VERSION 5.7 ;
  NOWIREEXTENSIONATPIN ON ;
  DIVIDERCHAR "/" ;
  BUSBITCHARS "[]" ;
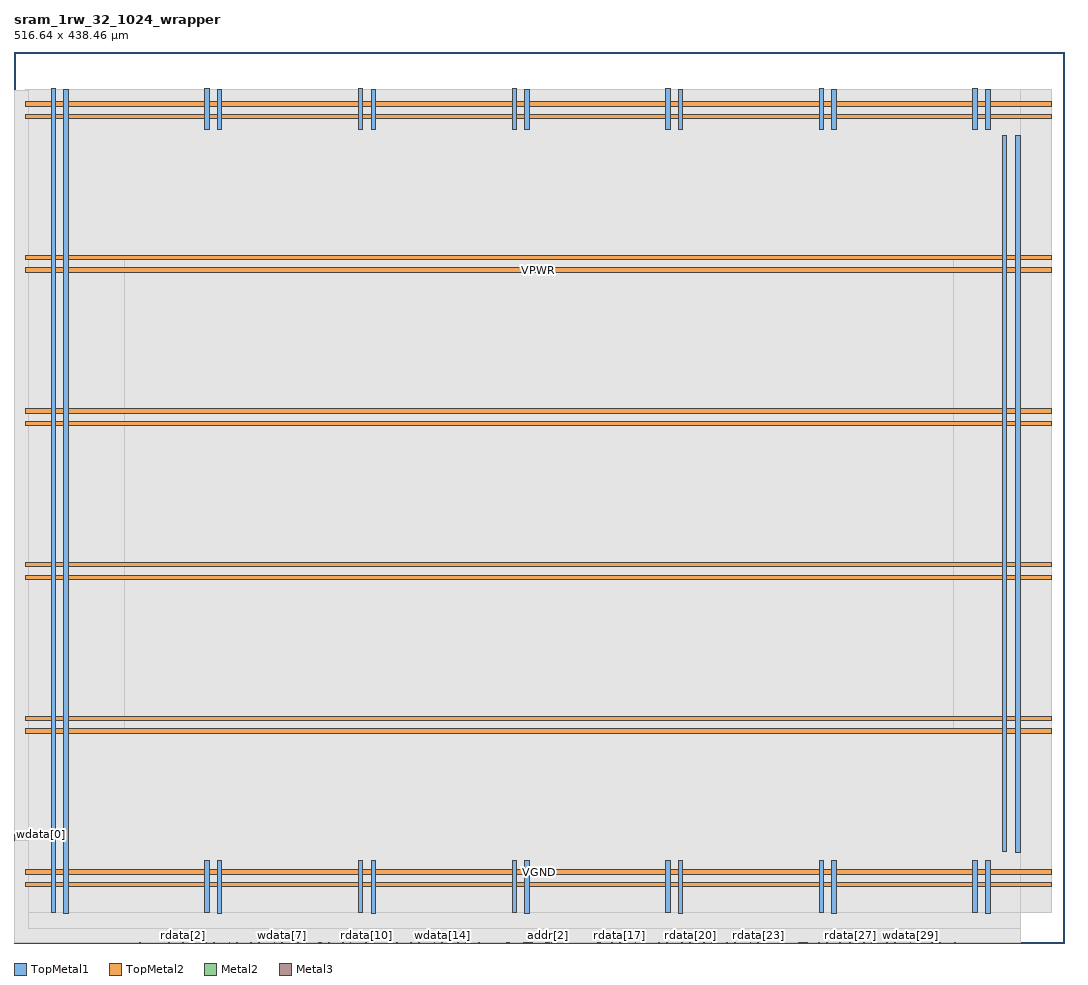
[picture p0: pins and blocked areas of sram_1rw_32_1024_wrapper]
MACRO sram_1rw_32_1024_wrapper
  CLASS BLOCK ;
  FOREIGN sram_1rw_32_1024_wrapper ;
  ORIGIN 0.000 0.000 ;
  SIZE 516.640 BY 438.460 ;
  PIN VGND
    DIRECTION INOUT ;
    USE GROUND ;
    PORT
      LAYER TopMetal1 ;
        RECT 24.460 14.490 26.660 419.800 ;
    END
    PORT
      LAYER TopMetal1 ;
        RECT 100.060 14.490 102.260 40.360 ;
    END
    PORT
      LAYER TopMetal1 ;
        RECT 100.060 400.050 102.260 419.800 ;
    END
    PORT
      LAYER TopMetal1 ;
        RECT 175.660 14.490 177.860 40.360 ;
    END
    PORT
      LAYER TopMetal1 ;
        RECT 175.660 400.050 177.860 419.800 ;
    END
    PORT
      LAYER TopMetal1 ;
        RECT 251.260 14.490 253.460 40.360 ;
    END
    PORT
      LAYER TopMetal1 ;
        RECT 251.260 400.050 253.460 419.800 ;
    END
    PORT
      LAYER TopMetal1 ;
        RECT 326.860 14.490 329.060 40.360 ;
    END
    PORT
      LAYER TopMetal1 ;
        RECT 326.860 400.050 329.060 419.800 ;
    END
    PORT
      LAYER TopMetal1 ;
        RECT 402.460 14.490 404.660 40.360 ;
    END
    PORT
      LAYER TopMetal1 ;
        RECT 402.460 400.050 404.660 419.800 ;
    END
    PORT
      LAYER TopMetal1 ;
        RECT 478.060 14.490 480.260 40.360 ;
    END
    PORT
      LAYER TopMetal1 ;
        RECT 478.060 400.050 480.260 419.800 ;
    END
    PORT
      LAYER TopMetal2 ;
        RECT 5.760 33.820 510.720 36.020 ;
    END
    PORT
      LAYER TopMetal2 ;
        RECT 5.760 109.420 510.720 111.620 ;
    END
    PORT
      LAYER TopMetal2 ;
        RECT 5.760 185.020 510.720 187.220 ;
    END
    PORT
      LAYER TopMetal2 ;
        RECT 5.760 260.620 510.720 262.820 ;
    END
    PORT
      LAYER TopMetal2 ;
        RECT 5.760 336.220 510.720 338.420 ;
    END
    PORT
      LAYER TopMetal2 ;
        RECT 5.760 411.820 510.720 414.020 ;
    END
    PORT
      LAYER TopMetal1 ;
        RECT 493.020 44.730 495.220 397.120 ;
    END
  END VGND
  PIN VPWR
    DIRECTION INOUT ;
    USE POWER ;
    PORT
      LAYER TopMetal1 ;
        RECT 18.260 14.900 20.460 420.210 ;
    END
    PORT
      LAYER TopMetal1 ;
        RECT 93.860 14.900 96.060 40.360 ;
    END
    PORT
      LAYER TopMetal1 ;
        RECT 93.860 400.100 96.060 420.210 ;
    END
    PORT
      LAYER TopMetal1 ;
        RECT 169.460 14.900 171.660 40.360 ;
    END
    PORT
      LAYER TopMetal1 ;
        RECT 169.460 400.100 171.660 420.210 ;
    END
    PORT
      LAYER TopMetal1 ;
        RECT 245.060 14.900 247.260 40.360 ;
    END
    PORT
      LAYER TopMetal1 ;
        RECT 245.060 400.100 247.260 420.210 ;
    END
    PORT
      LAYER TopMetal1 ;
        RECT 320.660 14.900 322.860 40.360 ;
    END
    PORT
      LAYER TopMetal1 ;
        RECT 320.660 400.100 322.860 420.210 ;
    END
    PORT
      LAYER TopMetal1 ;
        RECT 396.260 14.900 398.460 40.360 ;
    END
    PORT
      LAYER TopMetal1 ;
        RECT 396.260 400.100 398.460 420.210 ;
    END
    PORT
      LAYER TopMetal1 ;
        RECT 471.860 14.900 474.060 40.360 ;
    END
    PORT
      LAYER TopMetal1 ;
        RECT 471.860 400.100 474.060 420.210 ;
    END
    PORT
      LAYER TopMetal2 ;
        RECT 5.760 27.620 510.720 29.820 ;
    END
    PORT
      LAYER TopMetal2 ;
        RECT 5.760 103.220 510.720 105.420 ;
    END
    PORT
      LAYER TopMetal2 ;
        RECT 5.760 178.820 510.720 181.020 ;
    END
    PORT
      LAYER TopMetal2 ;
        RECT 5.760 254.420 510.720 256.620 ;
    END
    PORT
      LAYER TopMetal2 ;
        RECT 5.760 330.020 510.720 332.220 ;
    END
    PORT
      LAYER TopMetal2 ;
        RECT 5.760 405.620 510.720 407.820 ;
    END
    PORT
      LAYER TopMetal1 ;
        RECT 486.180 45.140 488.380 397.530 ;
    END
  END VPWR
  PIN addr[0]
    DIRECTION INPUT ;
    USE SIGNAL ;
    ANTENNAGATEAREA 0.180700 ;
    PORT
      LAYER Metal2 ;
        RECT 254.680 0.000 255.080 0.400 ;
    END
  END addr[0]
  PIN addr[1]
    DIRECTION INPUT ;
    USE SIGNAL ;
    ANTENNAGATEAREA 0.180700 ;
    PORT
      LAYER Metal2 ;
        RECT 253.720 0.000 254.120 0.400 ;
    END
  END addr[1]
  PIN addr[2]
    DIRECTION INPUT ;
    USE SIGNAL ;
    ANTENNAGATEAREA 0.180700 ;
    PORT
      LAYER Metal2 ;
        RECT 262.360 0.000 262.760 0.400 ;
    END
  END addr[2]
  PIN addr[3]
    DIRECTION INPUT ;
    USE SIGNAL ;
    ANTENNAGATEAREA 0.180700 ;
    PORT
      LAYER Metal2 ;
        RECT 261.400 0.000 261.800 0.400 ;
    END
  END addr[3]
  PIN addr[4]
    DIRECTION INPUT ;
    USE SIGNAL ;
    ANTENNAGATEAREA 0.180700 ;
    PORT
      LAYER Metal2 ;
        RECT 264.280 0.000 264.680 0.400 ;
    END
  END addr[4]
  PIN addr[5]
    DIRECTION INPUT ;
    USE SIGNAL ;
    ANTENNAGATEAREA 0.180700 ;
    PORT
      LAYER Metal2 ;
        RECT 263.320 0.000 263.720 0.400 ;
    END
  END addr[5]
  PIN addr[6]
    DIRECTION INPUT ;
    USE SIGNAL ;
    ANTENNAGATEAREA 0.180700 ;
    PORT
      LAYER Metal2 ;
        RECT 242.200 0.000 242.600 0.400 ;
    END
  END addr[6]
  PIN addr[7]
    DIRECTION INPUT ;
    USE SIGNAL ;
    ANTENNAGATEAREA 0.180700 ;
    PORT
      LAYER Metal2 ;
        RECT 243.160 0.000 243.560 0.400 ;
    END
  END addr[7]
  PIN addr[8]
    DIRECTION INPUT ;
    USE SIGNAL ;
    ANTENNAGATEAREA 0.180700 ;
    PORT
      LAYER Metal2 ;
        RECT 271.960 0.000 272.360 0.400 ;
    END
  END addr[8]
  PIN addr[9]
    DIRECTION INPUT ;
    USE SIGNAL ;
    ANTENNAGATEAREA 0.180700 ;
    PORT
      LAYER Metal2 ;
        RECT 267.160 0.000 267.560 0.400 ;
    END
  END addr[9]
  PIN clk
    DIRECTION INPUT ;
    USE SIGNAL ;
    ANTENNAGATEAREA 0.200850 ;
    PORT
      LAYER Metal2 ;
        RECT 252.760 0.000 253.160 0.400 ;
    END
  END clk
  PIN cs
    DIRECTION INPUT ;
    USE SIGNAL ;
    ANTENNAGATEAREA 0.180700 ;
    PORT
      LAYER Metal2 ;
        RECT 250.840 0.000 251.240 0.400 ;
    END
  END cs
  PIN rdata[0]
    DIRECTION OUTPUT ;
    USE SIGNAL ;
    ANTENNADIFFAREA 0.708600 ;
    PORT
      LAYER Metal3 ;
        RECT 0.000 50.620 0.400 51.020 ;
    END
  END rdata[0]
  PIN rdata[10]
    DIRECTION OUTPUT ;
    USE SIGNAL ;
    ANTENNADIFFAREA 0.708600 ;
    PORT
      LAYER Metal2 ;
        RECT 173.080 0.000 173.480 0.400 ;
    END
  END rdata[10]
  PIN rdata[11]
    DIRECTION OUTPUT ;
    USE SIGNAL ;
    ANTENNADIFFAREA 0.708600 ;
    PORT
      LAYER Metal2 ;
        RECT 184.600 0.000 185.000 0.400 ;
    END
  END rdata[11]
  PIN rdata[12]
    DIRECTION OUTPUT ;
    USE SIGNAL ;
    ANTENNADIFFAREA 0.708600 ;
    PORT
      LAYER Metal2 ;
        RECT 195.160 0.000 195.560 0.400 ;
    END
  END rdata[12]
  PIN rdata[13]
    DIRECTION OUTPUT ;
    USE SIGNAL ;
    ANTENNADIFFAREA 0.708600 ;
    PORT
      LAYER Metal2 ;
        RECT 206.680 0.000 207.080 0.400 ;
    END
  END rdata[13]
  PIN rdata[14]
    DIRECTION OUTPUT ;
    USE SIGNAL ;
    ANTENNADIFFAREA 0.708600 ;
    PORT
      LAYER Metal2 ;
        RECT 218.200 0.000 218.600 0.400 ;
    END
  END rdata[14]
  PIN rdata[15]
    DIRECTION OUTPUT ;
    USE SIGNAL ;
    ANTENNADIFFAREA 0.708600 ;
    PORT
      LAYER Metal2 ;
        RECT 228.760 0.000 229.160 0.400 ;
    END
  END rdata[15]
  PIN rdata[16]
    DIRECTION OUTPUT ;
    USE SIGNAL ;
    ANTENNADIFFAREA 0.708600 ;
    PORT
      LAYER Metal2 ;
        RECT 287.320 0.000 287.720 0.400 ;
    END
  END rdata[16]
  PIN rdata[17]
    DIRECTION OUTPUT ;
    USE SIGNAL ;
    ANTENNADIFFAREA 0.708600 ;
    PORT
      LAYER Metal2 ;
        RECT 297.880 0.000 298.280 0.400 ;
    END
  END rdata[17]
  PIN rdata[18]
    DIRECTION OUTPUT ;
    USE SIGNAL ;
    ANTENNADIFFAREA 0.708600 ;
    PORT
      LAYER Metal2 ;
        RECT 309.400 0.000 309.800 0.400 ;
    END
  END rdata[18]
  PIN rdata[19]
    DIRECTION OUTPUT ;
    USE SIGNAL ;
    ANTENNADIFFAREA 0.708600 ;
    PORT
      LAYER Metal2 ;
        RECT 320.920 0.000 321.320 0.400 ;
    END
  END rdata[19]
  PIN rdata[1]
    DIRECTION OUTPUT ;
    USE SIGNAL ;
    ANTENNADIFFAREA 0.708600 ;
    PORT
      LAYER Metal3 ;
        RECT 0.000 52.300 0.400 52.700 ;
    END
  END rdata[1]
  PIN rdata[20]
    DIRECTION OUTPUT ;
    USE SIGNAL ;
    ANTENNADIFFAREA 0.708600 ;
    PORT
      LAYER Metal2 ;
        RECT 332.440 0.000 332.840 0.400 ;
    END
  END rdata[20]
  PIN rdata[21]
    DIRECTION OUTPUT ;
    USE SIGNAL ;
    ANTENNADIFFAREA 0.708600 ;
    PORT
      LAYER Metal2 ;
        RECT 343.000 0.000 343.400 0.400 ;
    END
  END rdata[21]
  PIN rdata[22]
    DIRECTION OUTPUT ;
    USE SIGNAL ;
    ANTENNADIFFAREA 0.708600 ;
    PORT
      LAYER Metal2 ;
        RECT 354.520 0.000 354.920 0.400 ;
    END
  END rdata[22]
  PIN rdata[23]
    DIRECTION OUTPUT ;
    USE SIGNAL ;
    ANTENNADIFFAREA 0.708600 ;
    PORT
      LAYER Metal2 ;
        RECT 366.040 0.000 366.440 0.400 ;
    END
  END rdata[23]
  PIN rdata[24]
    DIRECTION OUTPUT ;
    USE SIGNAL ;
    ANTENNADIFFAREA 0.708600 ;
    PORT
      LAYER Metal2 ;
        RECT 388.120 0.000 388.520 0.400 ;
    END
  END rdata[24]
  PIN rdata[25]
    DIRECTION OUTPUT ;
    USE SIGNAL ;
    ANTENNADIFFAREA 0.708600 ;
    PORT
      LAYER Metal2 ;
        RECT 389.080 0.000 389.480 0.400 ;
    END
  END rdata[25]
  PIN rdata[26]
    DIRECTION OUTPUT ;
    USE SIGNAL ;
    ANTENNADIFFAREA 0.708600 ;
    PORT
      LAYER Metal2 ;
        RECT 399.640 0.000 400.040 0.400 ;
    END
  END rdata[26]
  PIN rdata[27]
    DIRECTION OUTPUT ;
    USE SIGNAL ;
    ANTENNADIFFAREA 0.708600 ;
    PORT
      LAYER Metal2 ;
        RECT 411.160 0.000 411.560 0.400 ;
    END
  END rdata[27]
  PIN rdata[28]
    DIRECTION OUTPUT ;
    USE SIGNAL ;
    ANTENNADIFFAREA 0.708600 ;
    PORT
      LAYER Metal2 ;
        RECT 421.720 0.000 422.120 0.400 ;
    END
  END rdata[28]
  PIN rdata[29]
    DIRECTION OUTPUT ;
    USE SIGNAL ;
    ANTENNADIFFAREA 0.708600 ;
    PORT
      LAYER Metal2 ;
        RECT 433.240 0.000 433.640 0.400 ;
    END
  END rdata[29]
  PIN rdata[2]
    DIRECTION OUTPUT ;
    USE SIGNAL ;
    ANTENNADIFFAREA 0.708600 ;
    PORT
      LAYER Metal2 ;
        RECT 82.840 0.000 83.240 0.400 ;
    END
  END rdata[2]
  PIN rdata[30]
    DIRECTION OUTPUT ;
    USE SIGNAL ;
    ANTENNADIFFAREA 0.708600 ;
    PORT
      LAYER Metal2 ;
        RECT 444.760 0.000 445.160 0.400 ;
    END
  END rdata[30]
  PIN rdata[31]
    DIRECTION OUTPUT ;
    USE SIGNAL ;
    ANTENNADIFFAREA 0.708600 ;
    PORT
      LAYER Metal2 ;
        RECT 455.320 0.000 455.720 0.400 ;
    END
  END rdata[31]
  PIN rdata[3]
    DIRECTION OUTPUT ;
    USE SIGNAL ;
    ANTENNADIFFAREA 0.708600 ;
    PORT
      LAYER Metal2 ;
        RECT 94.360 0.000 94.760 0.400 ;
    END
  END rdata[3]
  PIN rdata[4]
    DIRECTION OUTPUT ;
    USE SIGNAL ;
    ANTENNADIFFAREA 0.708600 ;
    PORT
      LAYER Metal2 ;
        RECT 105.880 0.000 106.280 0.400 ;
    END
  END rdata[4]
  PIN rdata[5]
    DIRECTION OUTPUT ;
    USE SIGNAL ;
    ANTENNADIFFAREA 0.708600 ;
    PORT
      LAYER Metal2 ;
        RECT 116.440 0.000 116.840 0.400 ;
    END
  END rdata[5]
  PIN rdata[6]
    DIRECTION OUTPUT ;
    USE SIGNAL ;
    ANTENNADIFFAREA 0.708600 ;
    PORT
      LAYER Metal2 ;
        RECT 127.960 0.000 128.360 0.400 ;
    END
  END rdata[6]
  PIN rdata[7]
    DIRECTION OUTPUT ;
    USE SIGNAL ;
    ANTENNADIFFAREA 0.708600 ;
    PORT
      LAYER Metal2 ;
        RECT 139.480 0.000 139.880 0.400 ;
    END
  END rdata[7]
  PIN rdata[8]
    DIRECTION OUTPUT ;
    USE SIGNAL ;
    ANTENNADIFFAREA 0.708600 ;
    PORT
      LAYER Metal2 ;
        RECT 150.040 0.000 150.440 0.400 ;
    END
  END rdata[8]
  PIN rdata[9]
    DIRECTION OUTPUT ;
    USE SIGNAL ;
    ANTENNADIFFAREA 0.708600 ;
    PORT
      LAYER Metal2 ;
        RECT 161.560 0.000 161.960 0.400 ;
    END
  END rdata[9]
  PIN wdata[0]
    DIRECTION INPUT ;
    USE SIGNAL ;
    ANTENNAGATEAREA 0.180700 ;
    PORT
      LAYER Metal3 ;
        RECT 0.000 53.140 0.400 53.540 ;
    END
  END wdata[0]
  PIN wdata[10]
    DIRECTION INPUT ;
    USE SIGNAL ;
    ANTENNAGATEAREA 0.180700 ;
    PORT
      LAYER Metal2 ;
        RECT 165.400 0.000 165.800 0.400 ;
    END
  END wdata[10]
  PIN wdata[11]
    DIRECTION INPUT ;
    USE SIGNAL ;
    ANTENNAGATEAREA 0.180700 ;
    PORT
      LAYER Metal2 ;
        RECT 176.920 0.000 177.320 0.400 ;
    END
  END wdata[11]
  PIN wdata[12]
    DIRECTION INPUT ;
    USE SIGNAL ;
    ANTENNAGATEAREA 0.180700 ;
    PORT
      LAYER Metal2 ;
        RECT 188.440 0.000 188.840 0.400 ;
    END
  END wdata[12]
  PIN wdata[13]
    DIRECTION INPUT ;
    USE SIGNAL ;
    ANTENNAGATEAREA 0.180700 ;
    PORT
      LAYER Metal2 ;
        RECT 199.000 0.000 199.400 0.400 ;
    END
  END wdata[13]
  PIN wdata[14]
    DIRECTION INPUT ;
    USE SIGNAL ;
    ANTENNAGATEAREA 0.180700 ;
    PORT
      LAYER Metal2 ;
        RECT 210.520 0.000 210.920 0.400 ;
    END
  END wdata[14]
  PIN wdata[15]
    DIRECTION INPUT ;
    USE SIGNAL ;
    ANTENNAGATEAREA 0.180700 ;
    PORT
      LAYER Metal2 ;
        RECT 222.040 0.000 222.440 0.400 ;
    END
  END wdata[15]
  PIN wdata[16]
    DIRECTION INPUT ;
    USE SIGNAL ;
    ANTENNAGATEAREA 0.180700 ;
    PORT
      LAYER Metal2 ;
        RECT 294.040 0.000 294.440 0.400 ;
    END
  END wdata[16]
  PIN wdata[17]
    DIRECTION INPUT ;
    USE SIGNAL ;
    ANTENNAGATEAREA 0.180700 ;
    PORT
      LAYER Metal2 ;
        RECT 305.560 0.000 305.960 0.400 ;
    END
  END wdata[17]
  PIN wdata[18]
    DIRECTION INPUT ;
    USE SIGNAL ;
    ANTENNAGATEAREA 0.180700 ;
    PORT
      LAYER Metal2 ;
        RECT 317.080 0.000 317.480 0.400 ;
    END
  END wdata[18]
  PIN wdata[19]
    DIRECTION INPUT ;
    USE SIGNAL ;
    ANTENNAGATEAREA 0.180700 ;
    PORT
      LAYER Metal2 ;
        RECT 328.600 0.000 329.000 0.400 ;
    END
  END wdata[19]
  PIN wdata[1]
    DIRECTION INPUT ;
    USE SIGNAL ;
    ANTENNAGATEAREA 0.180700 ;
    PORT
      LAYER Metal3 ;
        RECT 0.000 51.460 0.400 51.860 ;
    END
  END wdata[1]
  PIN wdata[20]
    DIRECTION INPUT ;
    USE SIGNAL ;
    ANTENNAGATEAREA 0.180700 ;
    PORT
      LAYER Metal2 ;
        RECT 339.160 0.000 339.560 0.400 ;
    END
  END wdata[20]
  PIN wdata[21]
    DIRECTION INPUT ;
    USE SIGNAL ;
    ANTENNAGATEAREA 0.180700 ;
    PORT
      LAYER Metal2 ;
        RECT 350.680 0.000 351.080 0.400 ;
    END
  END wdata[21]
  PIN wdata[22]
    DIRECTION INPUT ;
    USE SIGNAL ;
    ANTENNAGATEAREA 0.180700 ;
    PORT
      LAYER Metal2 ;
        RECT 362.200 0.000 362.600 0.400 ;
    END
  END wdata[22]
  PIN wdata[23]
    DIRECTION INPUT ;
    USE SIGNAL ;
    ANTENNAGATEAREA 0.180700 ;
    PORT
      LAYER Metal2 ;
        RECT 387.160 0.000 387.560 0.400 ;
    END
  END wdata[23]
  PIN wdata[24]
    DIRECTION INPUT ;
    USE SIGNAL ;
    ANTENNAGATEAREA 0.180700 ;
    PORT
      LAYER Metal2 ;
        RECT 386.200 0.000 386.600 0.400 ;
    END
  END wdata[24]
  PIN wdata[25]
    DIRECTION INPUT ;
    USE SIGNAL ;
    ANTENNAGATEAREA 0.180700 ;
    PORT
      LAYER Metal2 ;
        RECT 395.800 0.000 396.200 0.400 ;
    END
  END wdata[25]
  PIN wdata[26]
    DIRECTION INPUT ;
    USE SIGNAL ;
    ANTENNAGATEAREA 0.180700 ;
    PORT
      LAYER Metal2 ;
        RECT 406.360 0.000 406.760 0.400 ;
    END
  END wdata[26]
  PIN wdata[27]
    DIRECTION INPUT ;
    USE SIGNAL ;
    ANTENNAGATEAREA 0.180700 ;
    PORT
      LAYER Metal2 ;
        RECT 417.880 0.000 418.280 0.400 ;
    END
  END wdata[27]
  PIN wdata[28]
    DIRECTION INPUT ;
    USE SIGNAL ;
    ANTENNAGATEAREA 0.180700 ;
    PORT
      LAYER Metal2 ;
        RECT 429.400 0.000 429.800 0.400 ;
    END
  END wdata[28]
  PIN wdata[29]
    DIRECTION INPUT ;
    USE SIGNAL ;
    ANTENNAGATEAREA 0.180700 ;
    PORT
      LAYER Metal2 ;
        RECT 440.920 0.000 441.320 0.400 ;
    END
  END wdata[29]
  PIN wdata[2]
    DIRECTION INPUT ;
    USE SIGNAL ;
    ANTENNAGATEAREA 0.180700 ;
    PORT
      LAYER Metal2 ;
        RECT 76.120 0.000 76.520 0.400 ;
    END
  END wdata[2]
  PIN wdata[30]
    DIRECTION INPUT ;
    USE SIGNAL ;
    ANTENNAGATEAREA 0.180700 ;
    PORT
      LAYER Metal2 ;
        RECT 451.480 0.000 451.880 0.400 ;
    END
  END wdata[30]
  PIN wdata[31]
    DIRECTION INPUT ;
    USE SIGNAL ;
    ANTENNAGATEAREA 0.180700 ;
    PORT
      LAYER Metal2 ;
        RECT 463.000 0.000 463.400 0.400 ;
    END
  END wdata[31]
  PIN wdata[3]
    DIRECTION INPUT ;
    USE SIGNAL ;
    ANTENNAGATEAREA 0.180700 ;
    PORT
      LAYER Metal2 ;
        RECT 86.680 0.000 87.080 0.400 ;
    END
  END wdata[3]
  PIN wdata[4]
    DIRECTION INPUT ;
    USE SIGNAL ;
    ANTENNAGATEAREA 0.180700 ;
    PORT
      LAYER Metal2 ;
        RECT 98.200 0.000 98.600 0.400 ;
    END
  END wdata[4]
  PIN wdata[5]
    DIRECTION INPUT ;
    USE SIGNAL ;
    ANTENNAGATEAREA 0.180700 ;
    PORT
      LAYER Metal2 ;
        RECT 109.720 0.000 110.120 0.400 ;
    END
  END wdata[5]
  PIN wdata[6]
    DIRECTION INPUT ;
    USE SIGNAL ;
    ANTENNAGATEAREA 0.180700 ;
    PORT
      LAYER Metal2 ;
        RECT 120.280 0.000 120.680 0.400 ;
    END
  END wdata[6]
  PIN wdata[7]
    DIRECTION INPUT ;
    USE SIGNAL ;
    ANTENNAGATEAREA 0.180700 ;
    PORT
      LAYER Metal2 ;
        RECT 131.800 0.000 132.200 0.400 ;
    END
  END wdata[7]
  PIN wdata[8]
    DIRECTION INPUT ;
    USE SIGNAL ;
    ANTENNAGATEAREA 0.180700 ;
    PORT
      LAYER Metal2 ;
        RECT 143.320 0.000 143.720 0.400 ;
    END
  END wdata[8]
  PIN wdata[9]
    DIRECTION INPUT ;
    USE SIGNAL ;
    ANTENNAGATEAREA 0.180700 ;
    PORT
      LAYER Metal2 ;
        RECT 154.840 0.000 155.240 0.400 ;
    END
  END wdata[9]
  PIN we
    DIRECTION INPUT ;
    USE SIGNAL ;
    ANTENNAGATEAREA 0.180700 ;
    PORT
      LAYER Metal2 ;
        RECT 251.800 0.000 252.200 0.400 ;
    END
  END we
  PIN wmask[0]
    DIRECTION INPUT ;
    USE SIGNAL ;
    ANTENNAGATEAREA 0.180700 ;
    PORT
      LAYER Metal2 ;
        RECT 61.720 0.000 62.120 0.400 ;
    END
  END wmask[0]
  PIN wmask[1]
    DIRECTION INPUT ;
    USE SIGNAL ;
    ANTENNAGATEAREA 0.180700 ;
    PORT
      LAYER Metal2 ;
        RECT 151.000 0.000 151.400 0.400 ;
    END
  END wmask[1]
  PIN wmask[2]
    DIRECTION INPUT ;
    USE SIGNAL ;
    ANTENNAGATEAREA 0.180700 ;
    PORT
      LAYER Metal2 ;
        RECT 288.280 0.000 288.680 0.400 ;
    END
  END wmask[2]
  PIN wmask[3]
    DIRECTION INPUT ;
    USE SIGNAL ;
    ANTENNAGATEAREA 0.180700 ;
    PORT
      LAYER Metal2 ;
        RECT 390.040 0.000 390.440 0.400 ;
    END
  END wmask[3]
  OBS
      LAYER GatPoly ;
        RECT 5.760 14.970 510.720 419.730 ;
      LAYER Metal1 ;
        RECT 5.760 14.900 510.720 419.800 ;
      LAYER Metal2 ;
        RECT 6.135 0.610 495.040 419.725 ;
        RECT 6.135 0.100 61.510 0.610 ;
        RECT 62.330 0.100 75.910 0.610 ;
        RECT 76.730 0.100 82.630 0.610 ;
        RECT 83.450 0.100 86.470 0.610 ;
        RECT 87.290 0.100 94.150 0.610 ;
        RECT 94.970 0.100 97.990 0.610 ;
        RECT 98.810 0.100 105.670 0.610 ;
        RECT 106.490 0.100 109.510 0.610 ;
        RECT 110.330 0.100 116.230 0.610 ;
        RECT 117.050 0.100 120.070 0.610 ;
        RECT 120.890 0.100 127.750 0.610 ;
        RECT 128.570 0.100 131.590 0.610 ;
        RECT 132.410 0.100 139.270 0.610 ;
        RECT 140.090 0.100 143.110 0.610 ;
        RECT 143.930 0.100 149.830 0.610 ;
        RECT 150.650 0.100 150.790 0.610 ;
        RECT 151.610 0.100 154.630 0.610 ;
        RECT 155.450 0.100 161.350 0.610 ;
        RECT 162.170 0.100 165.190 0.610 ;
        RECT 166.010 0.100 172.870 0.610 ;
        RECT 173.690 0.100 176.710 0.610 ;
        RECT 177.530 0.100 184.390 0.610 ;
        RECT 185.210 0.100 188.230 0.610 ;
        RECT 189.050 0.100 194.950 0.610 ;
        RECT 195.770 0.100 198.790 0.610 ;
        RECT 199.610 0.100 206.470 0.610 ;
        RECT 207.290 0.100 210.310 0.610 ;
        RECT 211.130 0.100 217.990 0.610 ;
        RECT 218.810 0.100 221.830 0.610 ;
        RECT 222.650 0.100 228.550 0.610 ;
        RECT 229.370 0.100 241.990 0.610 ;
        RECT 242.810 0.100 242.950 0.610 ;
        RECT 243.770 0.100 250.630 0.610 ;
        RECT 251.450 0.100 251.590 0.610 ;
        RECT 252.410 0.100 252.550 0.610 ;
        RECT 253.370 0.100 253.510 0.610 ;
        RECT 254.330 0.100 254.470 0.610 ;
        RECT 255.290 0.100 261.190 0.610 ;
        RECT 262.010 0.100 262.150 0.610 ;
        RECT 262.970 0.100 263.110 0.610 ;
        RECT 263.930 0.100 264.070 0.610 ;
        RECT 264.890 0.100 266.950 0.610 ;
        RECT 267.770 0.100 271.750 0.610 ;
        RECT 272.570 0.100 287.110 0.610 ;
        RECT 287.930 0.100 288.070 0.610 ;
        RECT 288.890 0.100 293.830 0.610 ;
        RECT 294.650 0.100 297.670 0.610 ;
        RECT 298.490 0.100 305.350 0.610 ;
        RECT 306.170 0.100 309.190 0.610 ;
        RECT 310.010 0.100 316.870 0.610 ;
        RECT 317.690 0.100 320.710 0.610 ;
        RECT 321.530 0.100 328.390 0.610 ;
        RECT 329.210 0.100 332.230 0.610 ;
        RECT 333.050 0.100 338.950 0.610 ;
        RECT 339.770 0.100 342.790 0.610 ;
        RECT 343.610 0.100 350.470 0.610 ;
        RECT 351.290 0.100 354.310 0.610 ;
        RECT 355.130 0.100 361.990 0.610 ;
        RECT 362.810 0.100 365.830 0.610 ;
        RECT 366.650 0.100 385.990 0.610 ;
        RECT 386.810 0.100 386.950 0.610 ;
        RECT 387.770 0.100 387.910 0.610 ;
        RECT 388.730 0.100 388.870 0.610 ;
        RECT 389.690 0.100 389.830 0.610 ;
        RECT 390.650 0.100 395.590 0.610 ;
        RECT 396.410 0.100 399.430 0.610 ;
        RECT 400.250 0.100 406.150 0.610 ;
        RECT 406.970 0.100 410.950 0.610 ;
        RECT 411.770 0.100 417.670 0.610 ;
        RECT 418.490 0.100 421.510 0.610 ;
        RECT 422.330 0.100 429.190 0.610 ;
        RECT 430.010 0.100 433.030 0.610 ;
        RECT 433.850 0.100 440.710 0.610 ;
        RECT 441.530 0.100 444.550 0.610 ;
        RECT 445.370 0.100 451.270 0.610 ;
        RECT 452.090 0.100 455.110 0.610 ;
        RECT 455.930 0.100 462.790 0.610 ;
        RECT 463.610 0.100 495.040 0.610 ;
      LAYER Metal3 ;
        RECT 0.400 53.750 495.085 419.680 ;
        RECT 0.610 52.930 495.085 53.750 ;
        RECT 0.400 52.910 495.085 52.930 ;
        RECT 0.610 52.090 495.085 52.910 ;
        RECT 0.400 52.070 495.085 52.090 ;
        RECT 0.610 51.250 495.085 52.070 ;
        RECT 0.400 51.230 495.085 51.250 ;
        RECT 0.610 50.410 495.085 51.230 ;
        RECT 0.400 0.320 495.085 50.410 ;
      LAYER Metal4 ;
        RECT 7.095 6.995 495.040 419.725 ;
      LAYER Metal5 ;
        RECT 7.055 14.810 495.085 419.890 ;
      LAYER TopMetal1 ;
        RECT 54.615 103.270 462.025 338.370 ;
  END
END sram_1rw_32_1024_wrapper
END LIBRARY

